# Generated by FakeRAM 2.0 (routing-friendly)
VERSION 5.7 ;
BUSBITCHARS "[]" ;
PROPERTYDEFINITIONS
  MACRO width INTEGER ;
  MACRO depth INTEGER ;
  MACRO banks INTEGER ;
END PROPERTYDEFINITIONS
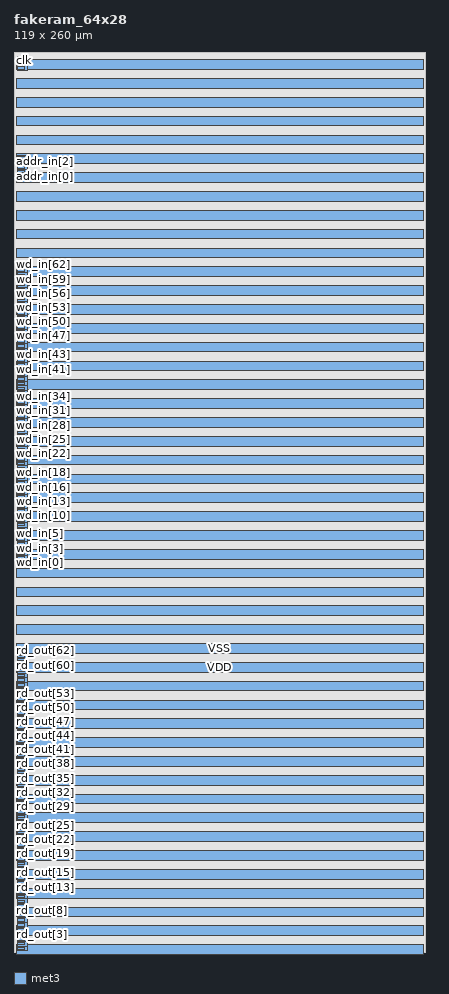
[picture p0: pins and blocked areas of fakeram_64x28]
MACRO fakeram_64x28
  PROPERTY width 64 ;
  PROPERTY depth 28 ;
  PROPERTY banks 1 ;
  FOREIGN fakeram_64x28 0 0 ;
  SYMMETRY X Y R90 ;
  SIZE 119.000 BY 260.000 ;
  CLASS BLOCK ;
  PIN rd_out[0]
    DIRECTION OUTPUT ;
    USE SIGNAL ;
    PORT
      LAYER met3 ;
      RECT 1.000 0.680 3.000 1.380 ;
    END
    PORT
      LAYER met3 ;
      RECT 1.000 0.330 4.000 1.730 ;
    END
  END rd_out[0]
  PIN rd_out[1]
    DIRECTION OUTPUT ;
    USE SIGNAL ;
    PORT
      LAYER met3 ;
      RECT 1.000 2.040 3.000 2.740 ;
    END
    PORT
      LAYER met3 ;
      RECT 1.000 1.690 4.000 3.090 ;
    END
  END rd_out[1]
  PIN rd_out[2]
    DIRECTION OUTPUT ;
    USE SIGNAL ;
    PORT
      LAYER met3 ;
      RECT 1.000 3.400 3.000 4.100 ;
    END
    PORT
      LAYER met3 ;
      RECT 1.000 3.050 4.000 4.450 ;
    END
  END rd_out[2]
  PIN rd_out[3]
    DIRECTION OUTPUT ;
    USE SIGNAL ;
    PORT
      LAYER met3 ;
      RECT 1.000 4.760 3.000 5.460 ;
    END
    PORT
      LAYER met3 ;
      RECT 1.000 4.410 4.000 5.810 ;
    END
  END rd_out[3]
  PIN rd_out[4]
    DIRECTION OUTPUT ;
    USE SIGNAL ;
    PORT
      LAYER met3 ;
      RECT 1.000 6.120 3.000 6.820 ;
    END
    PORT
      LAYER met3 ;
      RECT 1.000 5.770 4.000 7.170 ;
    END
  END rd_out[4]
  PIN rd_out[5]
    DIRECTION OUTPUT ;
    USE SIGNAL ;
    PORT
      LAYER met3 ;
      RECT 1.000 7.480 3.000 8.180 ;
    END
    PORT
      LAYER met3 ;
      RECT 1.000 7.130 4.000 8.530 ;
    END
  END rd_out[5]
  PIN rd_out[6]
    DIRECTION OUTPUT ;
    USE SIGNAL ;
    PORT
      LAYER met3 ;
      RECT 1.000 8.840 3.000 9.540 ;
    END
    PORT
      LAYER met3 ;
      RECT 1.000 8.490 4.000 9.890 ;
    END
  END rd_out[6]
  PIN rd_out[7]
    DIRECTION OUTPUT ;
    USE SIGNAL ;
    PORT
      LAYER met3 ;
      RECT 1.000 10.200 3.000 10.900 ;
    END
    PORT
      LAYER met3 ;
      RECT 1.000 9.850 4.000 11.250 ;
    END
  END rd_out[7]
  PIN rd_out[8]
    DIRECTION OUTPUT ;
    USE SIGNAL ;
    PORT
      LAYER met3 ;
      RECT 1.000 11.560 3.000 12.260 ;
    END
    PORT
      LAYER met3 ;
      RECT 1.000 11.210 4.000 12.610 ;
    END
  END rd_out[8]
  PIN rd_out[9]
    DIRECTION OUTPUT ;
    USE SIGNAL ;
    PORT
      LAYER met3 ;
      RECT 1.000 12.920 3.000 13.620 ;
    END
    PORT
      LAYER met3 ;
      RECT 1.000 12.570 4.000 13.970 ;
    END
  END rd_out[9]
  PIN rd_out[10]
    DIRECTION OUTPUT ;
    USE SIGNAL ;
    PORT
      LAYER met3 ;
      RECT 1.000 14.280 3.000 14.980 ;
    END
    PORT
      LAYER met3 ;
      RECT 1.000 13.930 4.000 15.330 ;
    END
  END rd_out[10]
  PIN rd_out[11]
    DIRECTION OUTPUT ;
    USE SIGNAL ;
    PORT
      LAYER met3 ;
      RECT 1.000 15.640 3.000 16.340 ;
    END
    PORT
      LAYER met3 ;
      RECT 1.000 15.290 4.000 16.690 ;
    END
  END rd_out[11]
  PIN rd_out[12]
    DIRECTION OUTPUT ;
    USE SIGNAL ;
    PORT
      LAYER met3 ;
      RECT 1.000 17.000 3.000 17.700 ;
    END
    PORT
      LAYER met3 ;
      RECT 1.000 16.650 4.000 18.050 ;
    END
  END rd_out[12]
  PIN rd_out[13]
    DIRECTION OUTPUT ;
    USE SIGNAL ;
    PORT
      LAYER met3 ;
      RECT 1.000 18.360 3.000 19.060 ;
    END
    PORT
      LAYER met3 ;
      RECT 1.000 18.010 4.000 19.410 ;
    END
  END rd_out[13]
  PIN rd_out[14]
    DIRECTION OUTPUT ;
    USE SIGNAL ;
    PORT
      LAYER met3 ;
      RECT 1.000 19.720 3.000 20.420 ;
    END
    PORT
      LAYER met3 ;
      RECT 1.000 19.370 4.000 20.770 ;
    END
  END rd_out[14]
  PIN rd_out[15]
    DIRECTION OUTPUT ;
    USE SIGNAL ;
    PORT
      LAYER met3 ;
      RECT 1.000 21.080 3.000 21.780 ;
    END
    PORT
      LAYER met3 ;
      RECT 1.000 20.730 4.000 22.130 ;
    END
  END rd_out[15]
  PIN rd_out[16]
    DIRECTION OUTPUT ;
    USE SIGNAL ;
    PORT
      LAYER met3 ;
      RECT 1.000 22.440 3.000 23.140 ;
    END
    PORT
      LAYER met3 ;
      RECT 1.000 22.090 4.000 23.490 ;
    END
  END rd_out[16]
  PIN rd_out[17]
    DIRECTION OUTPUT ;
    USE SIGNAL ;
    PORT
      LAYER met3 ;
      RECT 1.000 23.800 3.000 24.500 ;
    END
    PORT
      LAYER met3 ;
      RECT 1.000 23.450 4.000 24.850 ;
    END
  END rd_out[17]
  PIN rd_out[18]
    DIRECTION OUTPUT ;
    USE SIGNAL ;
    PORT
      LAYER met3 ;
      RECT 1.000 25.160 3.000 25.860 ;
    END
    PORT
      LAYER met3 ;
      RECT 1.000 24.810 4.000 26.210 ;
    END
  END rd_out[18]
  PIN rd_out[19]
    DIRECTION OUTPUT ;
    USE SIGNAL ;
    PORT
      LAYER met3 ;
      RECT 1.000 26.520 3.000 27.220 ;
    END
    PORT
      LAYER met3 ;
      RECT 1.000 26.170 4.000 27.570 ;
    END
  END rd_out[19]
  PIN rd_out[20]
    DIRECTION OUTPUT ;
    USE SIGNAL ;
    PORT
      LAYER met3 ;
      RECT 1.000 27.880 3.000 28.580 ;
    END
    PORT
      LAYER met3 ;
      RECT 1.000 27.530 4.000 28.930 ;
    END
  END rd_out[20]
  PIN rd_out[21]
    DIRECTION OUTPUT ;
    USE SIGNAL ;
    PORT
      LAYER met3 ;
      RECT 1.000 29.240 3.000 29.940 ;
    END
    PORT
      LAYER met3 ;
      RECT 1.000 28.890 4.000 30.290 ;
    END
  END rd_out[21]
  PIN rd_out[22]
    DIRECTION OUTPUT ;
    USE SIGNAL ;
    PORT
      LAYER met3 ;
      RECT 1.000 30.600 3.000 31.300 ;
    END
    PORT
      LAYER met3 ;
      RECT 1.000 30.250 4.000 31.650 ;
    END
  END rd_out[22]
  PIN rd_out[23]
    DIRECTION OUTPUT ;
    USE SIGNAL ;
    PORT
      LAYER met3 ;
      RECT 1.000 31.960 3.000 32.660 ;
    END
    PORT
      LAYER met3 ;
      RECT 1.000 31.610 4.000 33.010 ;
    END
  END rd_out[23]
  PIN rd_out[24]
    DIRECTION OUTPUT ;
    USE SIGNAL ;
    PORT
      LAYER met3 ;
      RECT 1.000 33.320 3.000 34.020 ;
    END
    PORT
      LAYER met3 ;
      RECT 1.000 32.970 4.000 34.370 ;
    END
  END rd_out[24]
  PIN rd_out[25]
    DIRECTION OUTPUT ;
    USE SIGNAL ;
    PORT
      LAYER met3 ;
      RECT 1.000 34.680 3.000 35.380 ;
    END
    PORT
      LAYER met3 ;
      RECT 1.000 34.330 4.000 35.730 ;
    END
  END rd_out[25]
  PIN rd_out[26]
    DIRECTION OUTPUT ;
    USE SIGNAL ;
    PORT
      LAYER met3 ;
      RECT 1.000 36.040 3.000 36.740 ;
    END
    PORT
      LAYER met3 ;
      RECT 1.000 35.690 4.000 37.090 ;
    END
  END rd_out[26]
  PIN rd_out[27]
    DIRECTION OUTPUT ;
    USE SIGNAL ;
    PORT
      LAYER met3 ;
      RECT 1.000 37.400 3.000 38.100 ;
    END
    PORT
      LAYER met3 ;
      RECT 1.000 37.050 4.000 38.450 ;
    END
  END rd_out[27]
  PIN rd_out[28]
    DIRECTION OUTPUT ;
    USE SIGNAL ;
    PORT
      LAYER met3 ;
      RECT 1.000 38.760 3.000 39.460 ;
    END
    PORT
      LAYER met3 ;
      RECT 1.000 38.410 4.000 39.810 ;
    END
  END rd_out[28]
  PIN rd_out[29]
    DIRECTION OUTPUT ;
    USE SIGNAL ;
    PORT
      LAYER met3 ;
      RECT 1.000 40.120 3.000 40.820 ;
    END
    PORT
      LAYER met3 ;
      RECT 1.000 39.770 4.000 41.170 ;
    END
  END rd_out[29]
  PIN rd_out[30]
    DIRECTION OUTPUT ;
    USE SIGNAL ;
    PORT
      LAYER met3 ;
      RECT 1.000 41.480 3.000 42.180 ;
    END
    PORT
      LAYER met3 ;
      RECT 1.000 41.130 4.000 42.530 ;
    END
  END rd_out[30]
  PIN rd_out[31]
    DIRECTION OUTPUT ;
    USE SIGNAL ;
    PORT
      LAYER met3 ;
      RECT 1.000 42.840 3.000 43.540 ;
    END
    PORT
      LAYER met3 ;
      RECT 1.000 42.490 4.000 43.890 ;
    END
  END rd_out[31]
  PIN rd_out[32]
    DIRECTION OUTPUT ;
    USE SIGNAL ;
    PORT
      LAYER met3 ;
      RECT 1.000 44.200 3.000 44.900 ;
    END
    PORT
      LAYER met3 ;
      RECT 1.000 43.850 4.000 45.250 ;
    END
  END rd_out[32]
  PIN rd_out[33]
    DIRECTION OUTPUT ;
    USE SIGNAL ;
    PORT
      LAYER met3 ;
      RECT 1.000 45.560 3.000 46.260 ;
    END
    PORT
      LAYER met3 ;
      RECT 1.000 45.210 4.000 46.610 ;
    END
  END rd_out[33]
  PIN rd_out[34]
    DIRECTION OUTPUT ;
    USE SIGNAL ;
    PORT
      LAYER met3 ;
      RECT 1.000 46.920 3.000 47.620 ;
    END
    PORT
      LAYER met3 ;
      RECT 1.000 46.570 4.000 47.970 ;
    END
  END rd_out[34]
  PIN rd_out[35]
    DIRECTION OUTPUT ;
    USE SIGNAL ;
    PORT
      LAYER met3 ;
      RECT 1.000 48.280 3.000 48.980 ;
    END
    PORT
      LAYER met3 ;
      RECT 1.000 47.930 4.000 49.330 ;
    END
  END rd_out[35]
  PIN rd_out[36]
    DIRECTION OUTPUT ;
    USE SIGNAL ;
    PORT
      LAYER met3 ;
      RECT 1.000 49.640 3.000 50.340 ;
    END
    PORT
      LAYER met3 ;
      RECT 1.000 49.290 4.000 50.690 ;
    END
  END rd_out[36]
  PIN rd_out[37]
    DIRECTION OUTPUT ;
    USE SIGNAL ;
    PORT
      LAYER met3 ;
      RECT 1.000 51.000 3.000 51.700 ;
    END
    PORT
      LAYER met3 ;
      RECT 1.000 50.650 4.000 52.050 ;
    END
  END rd_out[37]
  PIN rd_out[38]
    DIRECTION OUTPUT ;
    USE SIGNAL ;
    PORT
      LAYER met3 ;
      RECT 1.000 52.360 3.000 53.060 ;
    END
    PORT
      LAYER met3 ;
      RECT 1.000 52.010 4.000 53.410 ;
    END
  END rd_out[38]
  PIN rd_out[39]
    DIRECTION OUTPUT ;
    USE SIGNAL ;
    PORT
      LAYER met3 ;
      RECT 1.000 53.720 3.000 54.420 ;
    END
    PORT
      LAYER met3 ;
      RECT 1.000 53.370 4.000 54.770 ;
    END
  END rd_out[39]
  PIN rd_out[40]
    DIRECTION OUTPUT ;
    USE SIGNAL ;
    PORT
      LAYER met3 ;
      RECT 1.000 55.080 3.000 55.780 ;
    END
    PORT
      LAYER met3 ;
      RECT 1.000 54.730 4.000 56.130 ;
    END
  END rd_out[40]
  PIN rd_out[41]
    DIRECTION OUTPUT ;
    USE SIGNAL ;
    PORT
      LAYER met3 ;
      RECT 1.000 56.440 3.000 57.140 ;
    END
    PORT
      LAYER met3 ;
      RECT 1.000 56.090 4.000 57.490 ;
    END
  END rd_out[41]
  PIN rd_out[42]
    DIRECTION OUTPUT ;
    USE SIGNAL ;
    PORT
      LAYER met3 ;
      RECT 1.000 57.800 3.000 58.500 ;
    END
    PORT
      LAYER met3 ;
      RECT 1.000 57.450 4.000 58.850 ;
    END
  END rd_out[42]
  PIN rd_out[43]
    DIRECTION OUTPUT ;
    USE SIGNAL ;
    PORT
      LAYER met3 ;
      RECT 1.000 59.160 3.000 59.860 ;
    END
    PORT
      LAYER met3 ;
      RECT 1.000 58.810 4.000 60.210 ;
    END
  END rd_out[43]
  PIN rd_out[44]
    DIRECTION OUTPUT ;
    USE SIGNAL ;
    PORT
      LAYER met3 ;
      RECT 1.000 60.520 3.000 61.220 ;
    END
    PORT
      LAYER met3 ;
      RECT 1.000 60.170 4.000 61.570 ;
    END
  END rd_out[44]
  PIN rd_out[45]
    DIRECTION OUTPUT ;
    USE SIGNAL ;
    PORT
      LAYER met3 ;
      RECT 1.000 61.880 3.000 62.580 ;
    END
    PORT
      LAYER met3 ;
      RECT 1.000 61.530 4.000 62.930 ;
    END
  END rd_out[45]
  PIN rd_out[46]
    DIRECTION OUTPUT ;
    USE SIGNAL ;
    PORT
      LAYER met3 ;
      RECT 1.000 63.240 3.000 63.940 ;
    END
    PORT
      LAYER met3 ;
      RECT 1.000 62.890 4.000 64.290 ;
    END
  END rd_out[46]
  PIN rd_out[47]
    DIRECTION OUTPUT ;
    USE SIGNAL ;
    PORT
      LAYER met3 ;
      RECT 1.000 64.600 3.000 65.300 ;
    END
    PORT
      LAYER met3 ;
      RECT 1.000 64.250 4.000 65.650 ;
    END
  END rd_out[47]
  PIN rd_out[48]
    DIRECTION OUTPUT ;
    USE SIGNAL ;
    PORT
      LAYER met3 ;
      RECT 1.000 65.960 3.000 66.660 ;
    END
    PORT
      LAYER met3 ;
      RECT 1.000 65.610 4.000 67.010 ;
    END
  END rd_out[48]
  PIN rd_out[49]
    DIRECTION OUTPUT ;
    USE SIGNAL ;
    PORT
      LAYER met3 ;
      RECT 1.000 67.320 3.000 68.020 ;
    END
    PORT
      LAYER met3 ;
      RECT 1.000 66.970 4.000 68.370 ;
    END
  END rd_out[49]
  PIN rd_out[50]
    DIRECTION OUTPUT ;
    USE SIGNAL ;
    PORT
      LAYER met3 ;
      RECT 1.000 68.680 3.000 69.380 ;
    END
    PORT
      LAYER met3 ;
      RECT 1.000 68.330 4.000 69.730 ;
    END
  END rd_out[50]
  PIN rd_out[51]
    DIRECTION OUTPUT ;
    USE SIGNAL ;
    PORT
      LAYER met3 ;
      RECT 1.000 70.040 3.000 70.740 ;
    END
    PORT
      LAYER met3 ;
      RECT 1.000 69.690 4.000 71.090 ;
    END
  END rd_out[51]
  PIN rd_out[52]
    DIRECTION OUTPUT ;
    USE SIGNAL ;
    PORT
      LAYER met3 ;
      RECT 1.000 71.400 3.000 72.100 ;
    END
    PORT
      LAYER met3 ;
      RECT 1.000 71.050 4.000 72.450 ;
    END
  END rd_out[52]
  PIN rd_out[53]
    DIRECTION OUTPUT ;
    USE SIGNAL ;
    PORT
      LAYER met3 ;
      RECT 1.000 72.760 3.000 73.460 ;
    END
    PORT
      LAYER met3 ;
      RECT 1.000 72.410 4.000 73.810 ;
    END
  END rd_out[53]
  PIN rd_out[54]
    DIRECTION OUTPUT ;
    USE SIGNAL ;
    PORT
      LAYER met3 ;
      RECT 1.000 74.120 3.000 74.820 ;
    END
    PORT
      LAYER met3 ;
      RECT 1.000 73.770 4.000 75.170 ;
    END
  END rd_out[54]
  PIN rd_out[55]
    DIRECTION OUTPUT ;
    USE SIGNAL ;
    PORT
      LAYER met3 ;
      RECT 1.000 75.480 3.000 76.180 ;
    END
    PORT
      LAYER met3 ;
      RECT 1.000 75.130 4.000 76.530 ;
    END
  END rd_out[55]
  PIN rd_out[56]
    DIRECTION OUTPUT ;
    USE SIGNAL ;
    PORT
      LAYER met3 ;
      RECT 1.000 76.840 3.000 77.540 ;
    END
    PORT
      LAYER met3 ;
      RECT 1.000 76.490 4.000 77.890 ;
    END
  END rd_out[56]
  PIN rd_out[57]
    DIRECTION OUTPUT ;
    USE SIGNAL ;
    PORT
      LAYER met3 ;
      RECT 1.000 78.200 3.000 78.900 ;
    END
    PORT
      LAYER met3 ;
      RECT 1.000 77.850 4.000 79.250 ;
    END
  END rd_out[57]
  PIN rd_out[58]
    DIRECTION OUTPUT ;
    USE SIGNAL ;
    PORT
      LAYER met3 ;
      RECT 1.000 79.560 3.000 80.260 ;
    END
    PORT
      LAYER met3 ;
      RECT 1.000 79.210 4.000 80.610 ;
    END
  END rd_out[58]
  PIN rd_out[59]
    DIRECTION OUTPUT ;
    USE SIGNAL ;
    PORT
      LAYER met3 ;
      RECT 1.000 80.920 3.000 81.620 ;
    END
    PORT
      LAYER met3 ;
      RECT 1.000 80.570 4.000 81.970 ;
    END
  END rd_out[59]
  PIN rd_out[60]
    DIRECTION OUTPUT ;
    USE SIGNAL ;
    PORT
      LAYER met3 ;
      RECT 1.000 82.280 3.000 82.980 ;
    END
    PORT
      LAYER met3 ;
      RECT 1.000 81.930 4.000 83.330 ;
    END
  END rd_out[60]
  PIN rd_out[61]
    DIRECTION OUTPUT ;
    USE SIGNAL ;
    PORT
      LAYER met3 ;
      RECT 1.000 83.640 3.000 84.340 ;
    END
    PORT
      LAYER met3 ;
      RECT 1.000 83.290 4.000 84.690 ;
    END
  END rd_out[61]
  PIN rd_out[62]
    DIRECTION OUTPUT ;
    USE SIGNAL ;
    PORT
      LAYER met3 ;
      RECT 1.000 85.000 3.000 85.700 ;
    END
    PORT
      LAYER met3 ;
      RECT 1.000 84.650 4.000 86.050 ;
    END
  END rd_out[62]
  PIN rd_out[63]
    DIRECTION OUTPUT ;
    USE SIGNAL ;
    PORT
      LAYER met3 ;
      RECT 1.000 86.360 3.000 87.060 ;
    END
    PORT
      LAYER met3 ;
      RECT 1.000 86.010 4.000 87.410 ;
    END
  END rd_out[63]
  PIN wd_in[0]
    DIRECTION INPUT ;
    USE SIGNAL ;
    PORT
      LAYER met3 ;
      RECT 1.000 112.200 3.000 112.900 ;
    END
    PORT
      LAYER met3 ;
      RECT 1.000 111.850 4.000 113.250 ;
    END
  END wd_in[0]
  PIN wd_in[1]
    DIRECTION INPUT ;
    USE SIGNAL ;
    PORT
      LAYER met3 ;
      RECT 1.000 113.560 3.000 114.260 ;
    END
    PORT
      LAYER met3 ;
      RECT 1.000 113.210 4.000 114.610 ;
    END
  END wd_in[1]
  PIN wd_in[2]
    DIRECTION INPUT ;
    USE SIGNAL ;
    PORT
      LAYER met3 ;
      RECT 1.000 114.920 3.000 115.620 ;
    END
    PORT
      LAYER met3 ;
      RECT 1.000 114.570 4.000 115.970 ;
    END
  END wd_in[2]
  PIN wd_in[3]
    DIRECTION INPUT ;
    USE SIGNAL ;
    PORT
      LAYER met3 ;
      RECT 1.000 116.280 3.000 116.980 ;
    END
    PORT
      LAYER met3 ;
      RECT 1.000 115.930 4.000 117.330 ;
    END
  END wd_in[3]
  PIN wd_in[4]
    DIRECTION INPUT ;
    USE SIGNAL ;
    PORT
      LAYER met3 ;
      RECT 1.000 117.640 3.000 118.340 ;
    END
    PORT
      LAYER met3 ;
      RECT 1.000 117.290 4.000 118.690 ;
    END
  END wd_in[4]
  PIN wd_in[5]
    DIRECTION INPUT ;
    USE SIGNAL ;
    PORT
      LAYER met3 ;
      RECT 1.000 119.000 3.000 119.700 ;
    END
    PORT
      LAYER met3 ;
      RECT 1.000 118.650 4.000 120.050 ;
    END
  END wd_in[5]
  PIN wd_in[6]
    DIRECTION INPUT ;
    USE SIGNAL ;
    PORT
      LAYER met3 ;
      RECT 1.000 120.360 3.000 121.060 ;
    END
    PORT
      LAYER met3 ;
      RECT 1.000 120.010 4.000 121.410 ;
    END
  END wd_in[6]
  PIN wd_in[7]
    DIRECTION INPUT ;
    USE SIGNAL ;
    PORT
      LAYER met3 ;
      RECT 1.000 121.720 3.000 122.420 ;
    END
    PORT
      LAYER met3 ;
      RECT 1.000 121.370 4.000 122.770 ;
    END
  END wd_in[7]
  PIN wd_in[8]
    DIRECTION INPUT ;
    USE SIGNAL ;
    PORT
      LAYER met3 ;
      RECT 1.000 123.080 3.000 123.780 ;
    END
    PORT
      LAYER met3 ;
      RECT 1.000 122.730 4.000 124.130 ;
    END
  END wd_in[8]
  PIN wd_in[9]
    DIRECTION INPUT ;
    USE SIGNAL ;
    PORT
      LAYER met3 ;
      RECT 1.000 124.440 3.000 125.140 ;
    END
    PORT
      LAYER met3 ;
      RECT 1.000 124.090 4.000 125.490 ;
    END
  END wd_in[9]
  PIN wd_in[10]
    DIRECTION INPUT ;
    USE SIGNAL ;
    PORT
      LAYER met3 ;
      RECT 1.000 125.800 3.000 126.500 ;
    END
    PORT
      LAYER met3 ;
      RECT 1.000 125.450 4.000 126.850 ;
    END
  END wd_in[10]
  PIN wd_in[11]
    DIRECTION INPUT ;
    USE SIGNAL ;
    PORT
      LAYER met3 ;
      RECT 1.000 127.160 3.000 127.860 ;
    END
    PORT
      LAYER met3 ;
      RECT 1.000 126.810 4.000 128.210 ;
    END
  END wd_in[11]
  PIN wd_in[12]
    DIRECTION INPUT ;
    USE SIGNAL ;
    PORT
      LAYER met3 ;
      RECT 1.000 128.520 3.000 129.220 ;
    END
    PORT
      LAYER met3 ;
      RECT 1.000 128.170 4.000 129.570 ;
    END
  END wd_in[12]
  PIN wd_in[13]
    DIRECTION INPUT ;
    USE SIGNAL ;
    PORT
      LAYER met3 ;
      RECT 1.000 129.880 3.000 130.580 ;
    END
    PORT
      LAYER met3 ;
      RECT 1.000 129.530 4.000 130.930 ;
    END
  END wd_in[13]
  PIN wd_in[14]
    DIRECTION INPUT ;
    USE SIGNAL ;
    PORT
      LAYER met3 ;
      RECT 1.000 131.240 3.000 131.940 ;
    END
    PORT
      LAYER met3 ;
      RECT 1.000 130.890 4.000 132.290 ;
    END
  END wd_in[14]
  PIN wd_in[15]
    DIRECTION INPUT ;
    USE SIGNAL ;
    PORT
      LAYER met3 ;
      RECT 1.000 132.600 3.000 133.300 ;
    END
    PORT
      LAYER met3 ;
      RECT 1.000 132.250 4.000 133.650 ;
    END
  END wd_in[15]
  PIN wd_in[16]
    DIRECTION INPUT ;
    USE SIGNAL ;
    PORT
      LAYER met3 ;
      RECT 1.000 133.960 3.000 134.660 ;
    END
    PORT
      LAYER met3 ;
      RECT 1.000 133.610 4.000 135.010 ;
    END
  END wd_in[16]
  PIN wd_in[17]
    DIRECTION INPUT ;
    USE SIGNAL ;
    PORT
      LAYER met3 ;
      RECT 1.000 135.320 3.000 136.020 ;
    END
    PORT
      LAYER met3 ;
      RECT 1.000 134.970 4.000 136.370 ;
    END
  END wd_in[17]
  PIN wd_in[18]
    DIRECTION INPUT ;
    USE SIGNAL ;
    PORT
      LAYER met3 ;
      RECT 1.000 136.680 3.000 137.380 ;
    END
    PORT
      LAYER met3 ;
      RECT 1.000 136.330 4.000 137.730 ;
    END
  END wd_in[18]
  PIN wd_in[19]
    DIRECTION INPUT ;
    USE SIGNAL ;
    PORT
      LAYER met3 ;
      RECT 1.000 138.040 3.000 138.740 ;
    END
    PORT
      LAYER met3 ;
      RECT 1.000 137.690 4.000 139.090 ;
    END
  END wd_in[19]
  PIN wd_in[20]
    DIRECTION INPUT ;
    USE SIGNAL ;
    PORT
      LAYER met3 ;
      RECT 1.000 139.400 3.000 140.100 ;
    END
    PORT
      LAYER met3 ;
      RECT 1.000 139.050 4.000 140.450 ;
    END
  END wd_in[20]
  PIN wd_in[21]
    DIRECTION INPUT ;
    USE SIGNAL ;
    PORT
      LAYER met3 ;
      RECT 1.000 140.760 3.000 141.460 ;
    END
    PORT
      LAYER met3 ;
      RECT 1.000 140.410 4.000 141.810 ;
    END
  END wd_in[21]
  PIN wd_in[22]
    DIRECTION INPUT ;
    USE SIGNAL ;
    PORT
      LAYER met3 ;
      RECT 1.000 142.120 3.000 142.820 ;
    END
    PORT
      LAYER met3 ;
      RECT 1.000 141.770 4.000 143.170 ;
    END
  END wd_in[22]
  PIN wd_in[23]
    DIRECTION INPUT ;
    USE SIGNAL ;
    PORT
      LAYER met3 ;
      RECT 1.000 143.480 3.000 144.180 ;
    END
    PORT
      LAYER met3 ;
      RECT 1.000 143.130 4.000 144.530 ;
    END
  END wd_in[23]
  PIN wd_in[24]
    DIRECTION INPUT ;
    USE SIGNAL ;
    PORT
      LAYER met3 ;
      RECT 1.000 144.840 3.000 145.540 ;
    END
    PORT
      LAYER met3 ;
      RECT 1.000 144.490 4.000 145.890 ;
    END
  END wd_in[24]
  PIN wd_in[25]
    DIRECTION INPUT ;
    USE SIGNAL ;
    PORT
      LAYER met3 ;
      RECT 1.000 146.200 3.000 146.900 ;
    END
    PORT
      LAYER met3 ;
      RECT 1.000 145.850 4.000 147.250 ;
    END
  END wd_in[25]
  PIN wd_in[26]
    DIRECTION INPUT ;
    USE SIGNAL ;
    PORT
      LAYER met3 ;
      RECT 1.000 147.560 3.000 148.260 ;
    END
    PORT
      LAYER met3 ;
      RECT 1.000 147.210 4.000 148.610 ;
    END
  END wd_in[26]
  PIN wd_in[27]
    DIRECTION INPUT ;
    USE SIGNAL ;
    PORT
      LAYER met3 ;
      RECT 1.000 148.920 3.000 149.620 ;
    END
    PORT
      LAYER met3 ;
      RECT 1.000 148.570 4.000 149.970 ;
    END
  END wd_in[27]
  PIN wd_in[28]
    DIRECTION INPUT ;
    USE SIGNAL ;
    PORT
      LAYER met3 ;
      RECT 1.000 150.280 3.000 150.980 ;
    END
    PORT
      LAYER met3 ;
      RECT 1.000 149.930 4.000 151.330 ;
    END
  END wd_in[28]
  PIN wd_in[29]
    DIRECTION INPUT ;
    USE SIGNAL ;
    PORT
      LAYER met3 ;
      RECT 1.000 151.640 3.000 152.340 ;
    END
    PORT
      LAYER met3 ;
      RECT 1.000 151.290 4.000 152.690 ;
    END
  END wd_in[29]
  PIN wd_in[30]
    DIRECTION INPUT ;
    USE SIGNAL ;
    PORT
      LAYER met3 ;
      RECT 1.000 153.000 3.000 153.700 ;
    END
    PORT
      LAYER met3 ;
      RECT 1.000 152.650 4.000 154.050 ;
    END
  END wd_in[30]
  PIN wd_in[31]
    DIRECTION INPUT ;
    USE SIGNAL ;
    PORT
      LAYER met3 ;
      RECT 1.000 154.360 3.000 155.060 ;
    END
    PORT
      LAYER met3 ;
      RECT 1.000 154.010 4.000 155.410 ;
    END
  END wd_in[31]
  PIN wd_in[32]
    DIRECTION INPUT ;
    USE SIGNAL ;
    PORT
      LAYER met3 ;
      RECT 1.000 155.720 3.000 156.420 ;
    END
    PORT
      LAYER met3 ;
      RECT 1.000 155.370 4.000 156.770 ;
    END
  END wd_in[32]
  PIN wd_in[33]
    DIRECTION INPUT ;
    USE SIGNAL ;
    PORT
      LAYER met3 ;
      RECT 1.000 157.080 3.000 157.780 ;
    END
    PORT
      LAYER met3 ;
      RECT 1.000 156.730 4.000 158.130 ;
    END
  END wd_in[33]
  PIN wd_in[34]
    DIRECTION INPUT ;
    USE SIGNAL ;
    PORT
      LAYER met3 ;
      RECT 1.000 158.440 3.000 159.140 ;
    END
    PORT
      LAYER met3 ;
      RECT 1.000 158.090 4.000 159.490 ;
    END
  END wd_in[34]
  PIN wd_in[35]
    DIRECTION INPUT ;
    USE SIGNAL ;
    PORT
      LAYER met3 ;
      RECT 1.000 159.800 3.000 160.500 ;
    END
    PORT
      LAYER met3 ;
      RECT 1.000 159.450 4.000 160.850 ;
    END
  END wd_in[35]
  PIN wd_in[36]
    DIRECTION INPUT ;
    USE SIGNAL ;
    PORT
      LAYER met3 ;
      RECT 1.000 161.160 3.000 161.860 ;
    END
    PORT
      LAYER met3 ;
      RECT 1.000 160.810 4.000 162.210 ;
    END
  END wd_in[36]
  PIN wd_in[37]
    DIRECTION INPUT ;
    USE SIGNAL ;
    PORT
      LAYER met3 ;
      RECT 1.000 162.520 3.000 163.220 ;
    END
    PORT
      LAYER met3 ;
      RECT 1.000 162.170 4.000 163.570 ;
    END
  END wd_in[37]
  PIN wd_in[38]
    DIRECTION INPUT ;
    USE SIGNAL ;
    PORT
      LAYER met3 ;
      RECT 1.000 163.880 3.000 164.580 ;
    END
    PORT
      LAYER met3 ;
      RECT 1.000 163.530 4.000 164.930 ;
    END
  END wd_in[38]
  PIN wd_in[39]
    DIRECTION INPUT ;
    USE SIGNAL ;
    PORT
      LAYER met3 ;
      RECT 1.000 165.240 3.000 165.940 ;
    END
    PORT
      LAYER met3 ;
      RECT 1.000 164.890 4.000 166.290 ;
    END
  END wd_in[39]
  PIN wd_in[40]
    DIRECTION INPUT ;
    USE SIGNAL ;
    PORT
      LAYER met3 ;
      RECT 1.000 166.600 3.000 167.300 ;
    END
    PORT
      LAYER met3 ;
      RECT 1.000 166.250 4.000 167.650 ;
    END
  END wd_in[40]
  PIN wd_in[41]
    DIRECTION INPUT ;
    USE SIGNAL ;
    PORT
      LAYER met3 ;
      RECT 1.000 167.960 3.000 168.660 ;
    END
    PORT
      LAYER met3 ;
      RECT 1.000 167.610 4.000 169.010 ;
    END
  END wd_in[41]
  PIN wd_in[42]
    DIRECTION INPUT ;
    USE SIGNAL ;
    PORT
      LAYER met3 ;
      RECT 1.000 169.320 3.000 170.020 ;
    END
    PORT
      LAYER met3 ;
      RECT 1.000 168.970 4.000 170.370 ;
    END
  END wd_in[42]
  PIN wd_in[43]
    DIRECTION INPUT ;
    USE SIGNAL ;
    PORT
      LAYER met3 ;
      RECT 1.000 170.680 3.000 171.380 ;
    END
    PORT
      LAYER met3 ;
      RECT 1.000 170.330 4.000 171.730 ;
    END
  END wd_in[43]
  PIN wd_in[44]
    DIRECTION INPUT ;
    USE SIGNAL ;
    PORT
      LAYER met3 ;
      RECT 1.000 172.040 3.000 172.740 ;
    END
    PORT
      LAYER met3 ;
      RECT 1.000 171.690 4.000 173.090 ;
    END
  END wd_in[44]
  PIN wd_in[45]
    DIRECTION INPUT ;
    USE SIGNAL ;
    PORT
      LAYER met3 ;
      RECT 1.000 173.400 3.000 174.100 ;
    END
    PORT
      LAYER met3 ;
      RECT 1.000 173.050 4.000 174.450 ;
    END
  END wd_in[45]
  PIN wd_in[46]
    DIRECTION INPUT ;
    USE SIGNAL ;
    PORT
      LAYER met3 ;
      RECT 1.000 174.760 3.000 175.460 ;
    END
    PORT
      LAYER met3 ;
      RECT 1.000 174.410 4.000 175.810 ;
    END
  END wd_in[46]
  PIN wd_in[47]
    DIRECTION INPUT ;
    USE SIGNAL ;
    PORT
      LAYER met3 ;
      RECT 1.000 176.120 3.000 176.820 ;
    END
    PORT
      LAYER met3 ;
      RECT 1.000 175.770 4.000 177.170 ;
    END
  END wd_in[47]
  PIN wd_in[48]
    DIRECTION INPUT ;
    USE SIGNAL ;
    PORT
      LAYER met3 ;
      RECT 1.000 177.480 3.000 178.180 ;
    END
    PORT
      LAYER met3 ;
      RECT 1.000 177.130 4.000 178.530 ;
    END
  END wd_in[48]
  PIN wd_in[49]
    DIRECTION INPUT ;
    USE SIGNAL ;
    PORT
      LAYER met3 ;
      RECT 1.000 178.840 3.000 179.540 ;
    END
    PORT
      LAYER met3 ;
      RECT 1.000 178.490 4.000 179.890 ;
    END
  END wd_in[49]
  PIN wd_in[50]
    DIRECTION INPUT ;
    USE SIGNAL ;
    PORT
      LAYER met3 ;
      RECT 1.000 180.200 3.000 180.900 ;
    END
    PORT
      LAYER met3 ;
      RECT 1.000 179.850 4.000 181.250 ;
    END
  END wd_in[50]
  PIN wd_in[51]
    DIRECTION INPUT ;
    USE SIGNAL ;
    PORT
      LAYER met3 ;
      RECT 1.000 181.560 3.000 182.260 ;
    END
    PORT
      LAYER met3 ;
      RECT 1.000 181.210 4.000 182.610 ;
    END
  END wd_in[51]
  PIN wd_in[52]
    DIRECTION INPUT ;
    USE SIGNAL ;
    PORT
      LAYER met3 ;
      RECT 1.000 182.920 3.000 183.620 ;
    END
    PORT
      LAYER met3 ;
      RECT 1.000 182.570 4.000 183.970 ;
    END
  END wd_in[52]
  PIN wd_in[53]
    DIRECTION INPUT ;
    USE SIGNAL ;
    PORT
      LAYER met3 ;
      RECT 1.000 184.280 3.000 184.980 ;
    END
    PORT
      LAYER met3 ;
      RECT 1.000 183.930 4.000 185.330 ;
    END
  END wd_in[53]
  PIN wd_in[54]
    DIRECTION INPUT ;
    USE SIGNAL ;
    PORT
      LAYER met3 ;
      RECT 1.000 185.640 3.000 186.340 ;
    END
    PORT
      LAYER met3 ;
      RECT 1.000 185.290 4.000 186.690 ;
    END
  END wd_in[54]
  PIN wd_in[55]
    DIRECTION INPUT ;
    USE SIGNAL ;
    PORT
      LAYER met3 ;
      RECT 1.000 187.000 3.000 187.700 ;
    END
    PORT
      LAYER met3 ;
      RECT 1.000 186.650 4.000 188.050 ;
    END
  END wd_in[55]
  PIN wd_in[56]
    DIRECTION INPUT ;
    USE SIGNAL ;
    PORT
      LAYER met3 ;
      RECT 1.000 188.360 3.000 189.060 ;
    END
    PORT
      LAYER met3 ;
      RECT 1.000 188.010 4.000 189.410 ;
    END
  END wd_in[56]
  PIN wd_in[57]
    DIRECTION INPUT ;
    USE SIGNAL ;
    PORT
      LAYER met3 ;
      RECT 1.000 189.720 3.000 190.420 ;
    END
    PORT
      LAYER met3 ;
      RECT 1.000 189.370 4.000 190.770 ;
    END
  END wd_in[57]
  PIN wd_in[58]
    DIRECTION INPUT ;
    USE SIGNAL ;
    PORT
      LAYER met3 ;
      RECT 1.000 191.080 3.000 191.780 ;
    END
    PORT
      LAYER met3 ;
      RECT 1.000 190.730 4.000 192.130 ;
    END
  END wd_in[58]
  PIN wd_in[59]
    DIRECTION INPUT ;
    USE SIGNAL ;
    PORT
      LAYER met3 ;
      RECT 1.000 192.440 3.000 193.140 ;
    END
    PORT
      LAYER met3 ;
      RECT 1.000 192.090 4.000 193.490 ;
    END
  END wd_in[59]
  PIN wd_in[60]
    DIRECTION INPUT ;
    USE SIGNAL ;
    PORT
      LAYER met3 ;
      RECT 1.000 193.800 3.000 194.500 ;
    END
    PORT
      LAYER met3 ;
      RECT 1.000 193.450 4.000 194.850 ;
    END
  END wd_in[60]
  PIN wd_in[61]
    DIRECTION INPUT ;
    USE SIGNAL ;
    PORT
      LAYER met3 ;
      RECT 1.000 195.160 3.000 195.860 ;
    END
    PORT
      LAYER met3 ;
      RECT 1.000 194.810 4.000 196.210 ;
    END
  END wd_in[61]
  PIN wd_in[62]
    DIRECTION INPUT ;
    USE SIGNAL ;
    PORT
      LAYER met3 ;
      RECT 1.000 196.520 3.000 197.220 ;
    END
    PORT
      LAYER met3 ;
      RECT 1.000 196.170 4.000 197.570 ;
    END
  END wd_in[62]
  PIN wd_in[63]
    DIRECTION INPUT ;
    USE SIGNAL ;
    PORT
      LAYER met3 ;
      RECT 1.000 197.880 3.000 198.580 ;
    END
    PORT
      LAYER met3 ;
      RECT 1.000 197.530 4.000 198.930 ;
    END
  END wd_in[63]
  PIN addr_in[0]
    DIRECTION INPUT ;
    USE SIGNAL ;
    PORT
      LAYER met3 ;
      RECT 1.000 223.720 3.000 224.420 ;
    END
    PORT
      LAYER met3 ;
      RECT 1.000 223.370 4.000 224.770 ;
    END
  END addr_in[0]
  PIN addr_in[1]
    DIRECTION INPUT ;
    USE SIGNAL ;
    PORT
      LAYER met3 ;
      RECT 1.000 225.080 3.000 225.780 ;
    END
    PORT
      LAYER met3 ;
      RECT 1.000 224.730 4.000 226.130 ;
    END
  END addr_in[1]
  PIN addr_in[2]
    DIRECTION INPUT ;
    USE SIGNAL ;
    PORT
      LAYER met3 ;
      RECT 1.000 226.440 3.000 227.140 ;
    END
    PORT
      LAYER met3 ;
      RECT 1.000 226.090 4.000 227.490 ;
    END
  END addr_in[2]
  PIN addr_in[3]
    DIRECTION INPUT ;
    USE SIGNAL ;
    PORT
      LAYER met3 ;
      RECT 1.000 227.800 3.000 228.500 ;
    END
    PORT
      LAYER met3 ;
      RECT 1.000 227.450 4.000 228.850 ;
    END
  END addr_in[3]
  PIN addr_in[4]
    DIRECTION INPUT ;
    USE SIGNAL ;
    PORT
      LAYER met3 ;
      RECT 1.000 229.160 3.000 229.860 ;
    END
    PORT
      LAYER met3 ;
      RECT 1.000 228.810 4.000 230.210 ;
    END
  END addr_in[4]
  PIN we_in
    DIRECTION INPUT ;
    USE SIGNAL ;
    PORT
      LAYER met3 ;
      RECT 1.000 255.000 3.000 255.700 ;
    END
    PORT
      LAYER met3 ;
      RECT 1.000 254.650 4.000 256.050 ;
    END
  END we_in
  PIN ce_in
    DIRECTION INPUT ;
    USE SIGNAL ;
    PORT
      LAYER met3 ;
      RECT 1.000 256.360 3.000 257.060 ;
    END
    PORT
      LAYER met3 ;
      RECT 1.000 256.010 4.000 257.410 ;
    END
  END ce_in
  PIN clk
    DIRECTION INPUT ;
    USE SIGNAL ;
    PORT
      LAYER met3 ;
      RECT 1.000 257.720 3.000 258.420 ;
    END
    PORT
      LAYER met3 ;
      RECT 1.000 257.370 4.000 258.770 ;
    END
  END clk
  PIN VSS
    DIRECTION INOUT ;
    USE GROUND ;
    PORT
      LAYER met3 ;
      RECT 0.680 -0.720 118.320 2.080 ;
      RECT 0.680 10.160 118.320 12.960 ;
      RECT 0.680 21.040 118.320 23.840 ;
      RECT 0.680 31.920 118.320 34.720 ;
      RECT 0.680 42.800 118.320 45.600 ;
      RECT 0.680 53.680 118.320 56.480 ;
      RECT 0.680 64.560 118.320 67.360 ;
      RECT 0.680 75.440 118.320 78.240 ;
      RECT 0.680 86.320 118.320 89.120 ;
      RECT 0.680 97.200 118.320 100.000 ;
      RECT 0.680 108.080 118.320 110.880 ;
      RECT 0.680 118.960 118.320 121.760 ;
      RECT 0.680 129.840 118.320 132.640 ;
      RECT 0.680 140.720 118.320 143.520 ;
      RECT 0.680 151.600 118.320 154.400 ;
      RECT 0.680 162.480 118.320 165.280 ;
      RECT 0.680 173.360 118.320 176.160 ;
      RECT 0.680 184.240 118.320 187.040 ;
      RECT 0.680 195.120 118.320 197.920 ;
      RECT 0.680 206.000 118.320 208.800 ;
      RECT 0.680 216.880 118.320 219.680 ;
      RECT 0.680 227.760 118.320 230.560 ;
      RECT 0.680 238.640 118.320 241.440 ;
      RECT 0.680 249.520 118.320 252.320 ;
    END
  END VSS
  PIN VDD
    DIRECTION INOUT ;
    USE POWER ;
    PORT
      LAYER met3 ;
      RECT 0.680 4.720 118.320 7.520 ;
      RECT 0.680 15.600 118.320 18.400 ;
      RECT 0.680 26.480 118.320 29.280 ;
      RECT 0.680 37.360 118.320 40.160 ;
      RECT 0.680 48.240 118.320 51.040 ;
      RECT 0.680 59.120 118.320 61.920 ;
      RECT 0.680 70.000 118.320 72.800 ;
      RECT 0.680 80.880 118.320 83.680 ;
      RECT 0.680 91.760 118.320 94.560 ;
      RECT 0.680 102.640 118.320 105.440 ;
      RECT 0.680 113.520 118.320 116.320 ;
      RECT 0.680 124.400 118.320 127.200 ;
      RECT 0.680 135.280 118.320 138.080 ;
      RECT 0.680 146.160 118.320 148.960 ;
      RECT 0.680 157.040 118.320 159.840 ;
      RECT 0.680 167.920 118.320 170.720 ;
      RECT 0.680 178.800 118.320 181.600 ;
      RECT 0.680 189.680 118.320 192.480 ;
      RECT 0.680 200.560 118.320 203.360 ;
      RECT 0.680 211.440 118.320 214.240 ;
      RECT 0.680 222.320 118.320 225.120 ;
      RECT 0.680 233.200 118.320 236.000 ;
      RECT 0.680 244.080 118.320 246.880 ;
      RECT 0.680 254.960 118.320 257.760 ;
    END
  END VDD
  OBS
    LAYER met1 ;
    RECT 0 0 119.000 260.000 ;
    LAYER met2 ;
    RECT 0 0 119.000 260.000 ;
  END
END fakeram_64x28
END LIBRARY
